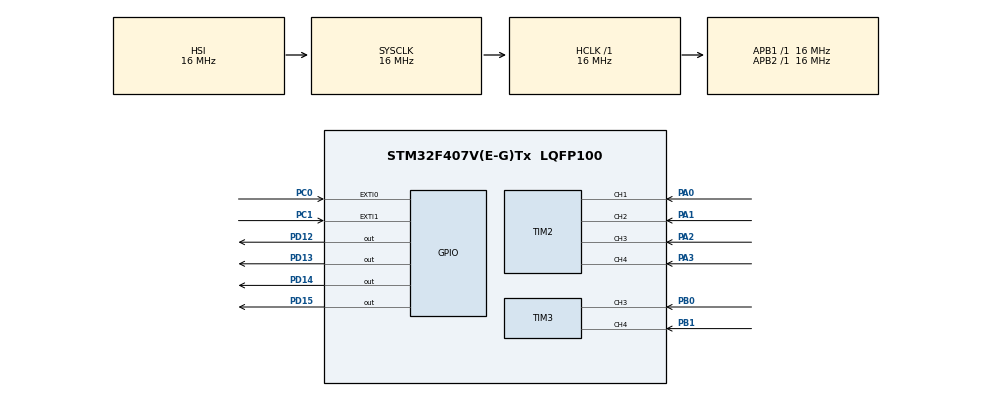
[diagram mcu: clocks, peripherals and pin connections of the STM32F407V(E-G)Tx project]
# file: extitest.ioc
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Mcu.Family=STM32F4
Mcu.Name=STM32F407V(E-G)Tx
Mcu.Package=LQFP100
NVIC.EXTI0_IRQn=true\:0\:0\:false\:false\:true\:true
NVIC.EXTI1_IRQn=true\:0\:0\:false\:false\:true\:true
NVIC.PriorityGroup=NVIC_PRIORITYGROUP_4
NVIC.TIM2_IRQn=true\:0\:0\:false\:false\:true\:true
NVIC.TIM3_IRQn=true\:0\:0\:false\:false\:true\:true
PA0-WKUP.GPIO_PuPd=GPIO_PULLDOWN
PA0-WKUP.Signal=S_TIM2_CH1_ETR
PA1.GPIO_PuPd=GPIO_PULLDOWN
PA1.Signal=S_TIM2_CH2
PA2.GPIO_PuPd=GPIO_PULLDOWN
PA2.Signal=S_TIM2_CH3
PA3.GPIO_PuPd=GPIO_PULLDOWN
PA3.Signal=S_TIM2_CH4
PB0.Signal=S_TIM3_CH3
PB1.Signal=S_TIM3_CH4
PC0.GPIO_PuPd=GPIO_PULLDOWN
PC0.Signal=GPXTI0
PC1.GPIO_PuPd=GPIO_PULLDOWN
PC1.Signal=GPXTI1
PD12.Signal=GPIO_Output
PD13.Signal=GPIO_Output
PD14.Signal=GPIO_Output
PD15.Signal=GPIO_Output
ProjectManager.HeapSize=0x200
ProjectManager.StackSize=0x400
ProjectManager.TargetToolchain=EWARM V7
RCC.AHBFreq_Value=16000000
RCC.APB1Freq_Value=16000000
RCC.APB2Freq_Value=16000000
RCC.CortexFreq_Value=16000000
RCC.HSE_VALUE=25000000
RCC.HSI_VALUE=16000000
RCC.LSE_VALUE=32768
RCC.SYSCLKFreq_VALUE=16000000
RCC.VCOOutputFreq_Value=192000000
SH.S_TIM2_CH1_ETR.0=TIM2_CH1,Input_Capture1_from_TI1
SH.S_TIM2_CH2.0=TIM2_CH2,Input_Capture2_from_TI2
SH.S_TIM2_CH3.0=TIM2_CH3,Input_Capture3_from_TI3
SH.S_TIM2_CH4.0=TIM2_CH4,Input_Capture4_from_TI4
SH.S_TIM3_CH3.0=TIM3_CH3,Input_Capture3_from_TI3
SH.S_TIM3_CH4.0=TIM3_CH4,Input_Capture4_from_TI4
TIM2.Channel-Input_Capture1_from_TI1=TIM_CHANNEL_1
TIM2.Channel-Input_Capture2_from_TI2=TIM_CHANNEL_2
TIM2.Channel-Input_Capture3_from_TI3=TIM_CHANNEL_3
TIM2.Channel-Input_Capture4_from_TI4=TIM_CHANNEL_4
TIM3.Channel-Input_Capture3_from_TI3=TIM_CHANNEL_3
TIM3.Channel-Input_Capture4_from_TI4=TIM_CHANNEL_4
board=custom

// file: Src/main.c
/**
  ******************************************************************************
  * @file           : main.c
  * @brief          : Main program body
  ******************************************************************************
  ** This notice applies to any and all portions of this file
  * that are not between comment pairs USER CODE BEGIN and
  * USER CODE END. Other portions of this file, whether
  * inserted by the user or by software development tools
  * are owned by their respective copyright owners.
  *
  * COPYRIGHT(c) 2018 STMicroelectronics
  *
  * Redistribution and use in source and binary forms, with or without modification,
  * are permitted provided that the following conditions are met:
  *   1. Redistributions of source code must retain the above copyright notice,
  *      this list of conditions and the following disclaimer.
  *   2. Redistributions in binary form must reproduce the above copyright notice,
  *      this list of conditions and the following disclaimer in the documentation
  *      and/or other materials provided with the distribution.
  *   3. Neither the name of STMicroelectronics nor the names of its contributors
  *      may be used to endorse or promote products derived from this software
  *      without specific prior written permission.
  *
  * THIS SOFTWARE IS PROVIDED BY THE COPYRIGHT HOLDERS AND CONTRIBUTORS "AS IS"
  * AND ANY EXPRESS OR IMPLIED WARRANTIES, INCLUDING, BUT NOT LIMITED TO, THE
  * IMPLIED WARRANTIES OF MERCHANTABILITY AND FITNESS FOR A PARTICULAR PURPOSE ARE
  * DISCLAIMED. IN NO EVENT SHALL THE COPYRIGHT HOLDER OR CONTRIBUTORS BE LIABLE
  * FOR ANY DIRECT, INDIRECT, INCIDENTAL, SPECIAL, EXEMPLARY, OR CONSEQUENTIAL
  * DAMAGES (INCLUDING, BUT NOT LIMITED TO, PROCUREMENT OF SUBSTITUTE GOODS OR
  * SERVICES; LOSS OF USE, DATA, OR PROFITS; OR BUSINESS INTERRUPTION) HOWEVER
  * CAUSED AND ON ANY THEORY OF LIABILITY, WHETHER IN CONTRACT, STRICT LIABILITY,
  * OR TORT (INCLUDING NEGLIGENCE OR OTHERWISE) ARISING IN ANY WAY OUT OF THE USE
  * OF THIS SOFTWARE, EVEN IF ADVISED OF THE POSSIBILITY OF SUCH DAMAGE.
  *
  ******************************************************************************
  */
#include "main.h"
#include "stm32f4xx_hal.h"

TIM_HandleTypeDef htim2;
TIM_HandleTypeDef htim3;

/* USER CODE BEGIN PV */
/* Private variables ---------------------------------------------------------*/

/* USER CODE END PV */

void SystemClock_Config(void);
static void MX_GPIO_Init(void);
static void MX_TIM3_Init(void);
static void MX_TIM2_Init(void);

/* USER CODE BEGIN PFP */
/* Private function prototypes -----------------------------------------------*/

/* USER CODE END PFP */

int main(void)
{

  /* MCU Configuration----------------------------------------------------------*/

  /* Reset of all peripherals, Initializes the Flash interface and the Systick. */
  HAL_Init();

  /* Configure the system clock */
  SystemClock_Config();

  /* Initialize all configured peripherals */
  MX_GPIO_Init();
  MX_TIM3_Init();
  MX_TIM2_Init();
  /* USER CODE BEGIN 2 */

  TIM2->CCER|=0x1111;
  TIM2->DIER|=0x2e; // tim2 IE
  TIM2->CR1|=0x01;

  TIM3->CCER|=0x1100;
  TIM3->DIER|=0x18;  // TIM3 ie
  TIM3->CR1|=0x01;
  /* USER CODE END 2 */

  /* Infinite loop */
  while (1)
  {

  }

}

void SystemClock_Config(void)
{

  RCC_OscInitTypeDef RCC_OscInitStruct;
  RCC_ClkInitTypeDef RCC_ClkInitStruct;

    /**Configure the main internal regulator output voltage
    */
  __HAL_RCC_PWR_CLK_ENABLE();

  __HAL_PWR_VOLTAGESCALING_CONFIG(PWR_REGULATOR_VOLTAGE_SCALE1);

    /**Initializes the CPU, AHB and APB busses clocks
    */
  RCC_OscInitStruct.OscillatorType = RCC_OSCILLATORTYPE_HSI;
  RCC_OscInitStruct.HSIState = RCC_HSI_ON;
  RCC_OscInitStruct.HSICalibrationValue = 16;
  RCC_OscInitStruct.PLL.PLLState = RCC_PLL_NONE;
  if (HAL_RCC_OscConfig(&RCC_OscInitStruct) != HAL_OK)
  {
    _Error_Handler(__FILE__, __LINE__);
  }

    /**Initializes the CPU, AHB and APB busses clocks
    */
  RCC_ClkInitStruct.ClockType = RCC_CLOCKTYPE_HCLK|RCC_CLOCKTYPE_SYSCLK
                              |RCC_CLOCKTYPE_PCLK1|RCC_CLOCKTYPE_PCLK2;
  RCC_ClkInitStruct.SYSCLKSource = RCC_SYSCLKSOURCE_HSI;
  RCC_ClkInitStruct.AHBCLKDivider = RCC_SYSCLK_DIV1;
  RCC_ClkInitStruct.APB1CLKDivider = RCC_HCLK_DIV1;
  RCC_ClkInitStruct.APB2CLKDivider = RCC_HCLK_DIV1;

  if (HAL_RCC_ClockConfig(&RCC_ClkInitStruct, FLASH_LATENCY_0) != HAL_OK)
  {
    _Error_Handler(__FILE__, __LINE__);
  }

    /**Configure the Systick interrupt time
    */
  HAL_SYSTICK_Config(HAL_RCC_GetHCLKFreq()/1000);

    /**Configure the Systick
    */
  HAL_SYSTICK_CLKSourceConfig(SYSTICK_CLKSOURCE_HCLK);

  /* SysTick_IRQn interrupt configuration */
  HAL_NVIC_SetPriority(SysTick_IRQn, 0, 0);
}

/* TIM2 init function */
static void MX_TIM2_Init(void)
{

  TIM_MasterConfigTypeDef sMasterConfig;
  TIM_IC_InitTypeDef sConfigIC;

  htim2.Instance = TIM2;
  htim2.Init.Prescaler = 0;
  htim2.Init.CounterMode = TIM_COUNTERMODE_UP;
  htim2.Init.Period = 65535;
  htim2.Init.ClockDivision = TIM_CLOCKDIVISION_DIV1;
  if (HAL_TIM_IC_Init(&htim2) != HAL_OK)
  {
    _Error_Handler(__FILE__, __LINE__);
  }

  sMasterConfig.MasterOutputTrigger = TIM_TRGO_RESET;
  sMasterConfig.MasterSlaveMode = TIM_MASTERSLAVEMODE_DISABLE;
  if (HAL_TIMEx_MasterConfigSynchronization(&htim2, &sMasterConfig) != HAL_OK)
  {
    _Error_Handler(__FILE__, __LINE__);
  }

  sConfigIC.ICPolarity = TIM_INPUTCHANNELPOLARITY_RISING;
  sConfigIC.ICSelection = TIM_ICSELECTION_DIRECTTI;
  sConfigIC.ICPrescaler = TIM_ICPSC_DIV1;
  sConfigIC.ICFilter = 0;
  if (HAL_TIM_IC_ConfigChannel(&htim2, &sConfigIC, TIM_CHANNEL_1) != HAL_OK)
  {
    _Error_Handler(__FILE__, __LINE__);
  }

  if (HAL_TIM_IC_ConfigChannel(&htim2, &sConfigIC, TIM_CHANNEL_2) != HAL_OK)
  {
    _Error_Handler(__FILE__, __LINE__);
  }

  if (HAL_TIM_IC_ConfigChannel(&htim2, &sConfigIC, TIM_CHANNEL_3) != HAL_OK)
  {
    _Error_Handler(__FILE__, __LINE__);
  }

  if (HAL_TIM_IC_ConfigChannel(&htim2, &sConfigIC, TIM_CHANNEL_4) != HAL_OK)
  {
    _Error_Handler(__FILE__, __LINE__);
  }

}

/* TIM3 init function */
static void MX_TIM3_Init(void)
{

  TIM_MasterConfigTypeDef sMasterConfig;
  TIM_IC_InitTypeDef sConfigIC;

  htim3.Instance = TIM3;
  htim3.Init.Prescaler = 0;
  htim3.Init.CounterMode = TIM_COUNTERMODE_UP;
  htim3.Init.Period = 65535;
  htim3.Init.ClockDivision = TIM_CLOCKDIVISION_DIV1;
  if (HAL_TIM_IC_Init(&htim3) != HAL_OK)
  {
    _Error_Handler(__FILE__, __LINE__);
  }

  sMasterConfig.MasterOutputTrigger = TIM_TRGO_RESET;
  sMasterConfig.MasterSlaveMode = TIM_MASTERSLAVEMODE_DISABLE;
  if (HAL_TIMEx_MasterConfigSynchronization(&htim3, &sMasterConfig) != HAL_OK)
  {
    _Error_Handler(__FILE__, __LINE__);
  }

  sConfigIC.ICPolarity = TIM_INPUTCHANNELPOLARITY_RISING;
  sConfigIC.ICSelection = TIM_ICSELECTION_DIRECTTI;
  sConfigIC.ICPrescaler = TIM_ICPSC_DIV1;
  sConfigIC.ICFilter = 0;
  if (HAL_TIM_IC_ConfigChannel(&htim3, &sConfigIC, TIM_CHANNEL_3) != HAL_OK)
  {
    _Error_Handler(__FILE__, __LINE__);
  }

  if (HAL_TIM_IC_ConfigChannel(&htim3, &sConfigIC, TIM_CHANNEL_4) != HAL_OK)
  {
    _Error_Handler(__FILE__, __LINE__);
  }

}

/** Configure pins as
        * Analog
        * Input
        * Output
        * EVENT_OUT
        * EXTI
*/
static void MX_GPIO_Init(void)
{

  GPIO_InitTypeDef GPIO_InitStruct;

  /* GPIO Ports Clock Enable */
  __HAL_RCC_GPIOC_CLK_ENABLE();
  __HAL_RCC_GPIOA_CLK_ENABLE();
  __HAL_RCC_GPIOB_CLK_ENABLE();
  __HAL_RCC_GPIOD_CLK_ENABLE();

  /*Configure GPIO pin Output Level */
  HAL_GPIO_WritePin(GPIOD, GPIO_PIN_12|GPIO_PIN_13|GPIO_PIN_14|GPIO_PIN_15, GPIO_PIN_RESET);

  /*Configure GPIO pins : PC0 PC1 */
  GPIO_InitStruct.Pin = GPIO_PIN_0|GPIO_PIN_1;
  GPIO_InitStruct.Mode = GPIO_MODE_IT_RISING;
  GPIO_InitStruct.Pull = GPIO_PULLDOWN;
  HAL_GPIO_Init(GPIOD, &GPIO_InitStruct);

  /*Configure GPIO pins : PD12 PD13 PD14 PD15 */
  GPIO_InitStruct.Pin = GPIO_PIN_12|GPIO_PIN_13|GPIO_PIN_14|GPIO_PIN_15;
  GPIO_InitStruct.Mode = GPIO_MODE_OUTPUT_PP;
  GPIO_InitStruct.Pull = GPIO_NOPULL;
  GPIO_InitStruct.Speed = GPIO_SPEED_FREQ_LOW;
  HAL_GPIO_Init(GPIOD, &GPIO_InitStruct);

  /* EXTI interrupt init*/
  HAL_NVIC_SetPriority(EXTI0_IRQn, 0, 0);
  HAL_NVIC_EnableIRQ(EXTI0_IRQn);

  HAL_NVIC_SetPriority(EXTI1_IRQn, 0, 0);
  HAL_NVIC_EnableIRQ(EXTI1_IRQn);

}

void _Error_Handler(char *file, int line)
{
  while(1)
  {
  }
}

/************************ (C) COPYRIGHT STMicroelectronics *****END OF FILE****/
